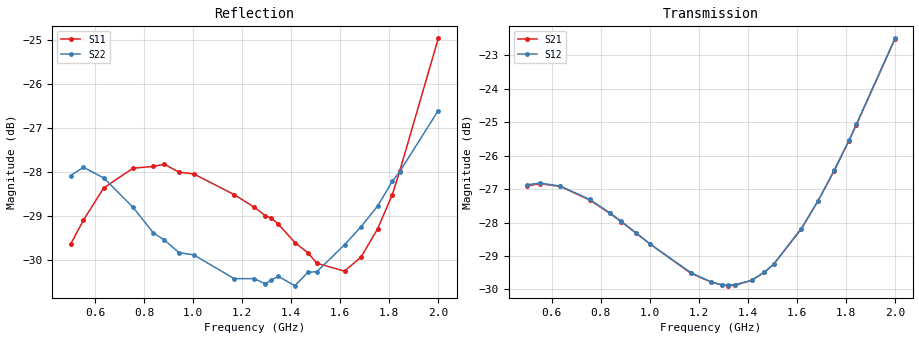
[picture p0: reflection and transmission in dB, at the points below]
!Agilent Technologies,E8363B,SG43030131,A.07.50.48
!Agilent E8363B: A.07.50.48
!Date: Wednesday, October 22, 2025 01:59:47
!Correction: S11(Full 2 Port(1,2))
!S21(Full 2 Port(1,2))
!S12(Full 2 Port(1,2))
!S22(Full 2 Port(1,2))
!S2P File: Measurements: S11, S21, S12, S22:
# Hz S  dB  R 50
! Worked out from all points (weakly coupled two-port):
!   201 points, 500 MHz to 2 GHz, reference 50 ohm
!   highest |S21| = -22.51 dB at 2 GHz (marker M1); lowest = -29.9 dB at 1.317 GHz (marker M2)
!   lowest |S11| = -30.3 dB at 1.617 GHz (marker M3), VSWR 1.06, Z = 48.5 - j2.61 ohm
!   |S11| at or under -10 dB: start of sweep to end of sweep
!   |S22| runs from -30.6 to -26.6 dB; largest |S21 - S12| = 0.0002
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5e8  -29.65 109.0  -26.90 -41.3  -26.87 -41.3  -28.09 162.3
5.525e8  -29.10 95.9  -26.84 -52.3  -26.82 -52.5  -27.90 152.5
6.35e8  -28.37 75.9  -26.92 -68.6  -26.91 -68.7  -28.14 137.4
7.55e8  -27.92 52.1  -27.33 -89.8  -27.31 -89.9  -28.81 116.5
8.375e8  -27.88 36.9  -27.73 -103.0  -27.71 -103.0  -29.39 102.2
8.825e8  -27.83 29.7  -27.97 -109.6  -27.96 -109.7  -29.55 94.3
9.425e8  -28.01 19.4  -28.31 -117.8  -28.30 -117.9  -29.84 84.2
1.0025e9  -28.05 9.4  -28.65 -125.4  -28.65 -125.5  -29.89 74.7
1.1675e9  -28.52 -18.2  -29.52 -142.7  -29.50 -142.8  -30.43 50.8
1.25e9  -28.81 -31.9  -29.78 -149.2  -29.78 -149.4  -30.43 39.2
1.295e9  -29.00 -40.8  -29.87 -152.4  -29.87 -152.5  -30.55 32.1
1.3175e9  -29.05 -45.1  -29.89 -153.9  -29.87 -154.0  -30.46 28.7
1.3475e9  -29.19 -50.4  -29.88 -155.8  -29.86 -155.9  -30.38 25.1
1.415e9  -29.61 -65.4  -29.73 -159.7  -29.73 -159.8  -30.59 14.5
1.4675e9  -29.84 -77.1  -29.49 -162.7  -29.48 -162.7  -30.29 6.1
1.505e9  -30.08 -86.8  -29.25 -164.8  -29.25 -164.9  -30.27 0.7
1.6175e9  -30.26 -118.6  -28.20 -172.0  -28.18 -172.1  -29.66 -17.7
1.685e9  -29.94 -140.2  -27.37 -177.2  -27.37 -177.2  -29.25 -29.6
1.7525e9  -29.30 -162.2  -26.45 176.8  -26.43 176.7  -28.78 -41.2
1.8125e9  -28.52 178.6  -25.55 170.6  -25.54 170.5  -28.22 -51.7
1.8425e9  -27.99 169.0  -25.08 167.3  -25.06 167.2  -28.00 -57.0
2e9  -24.97 123.0  -22.51 146.7  -22.49 146.7  -26.61 -87.7
